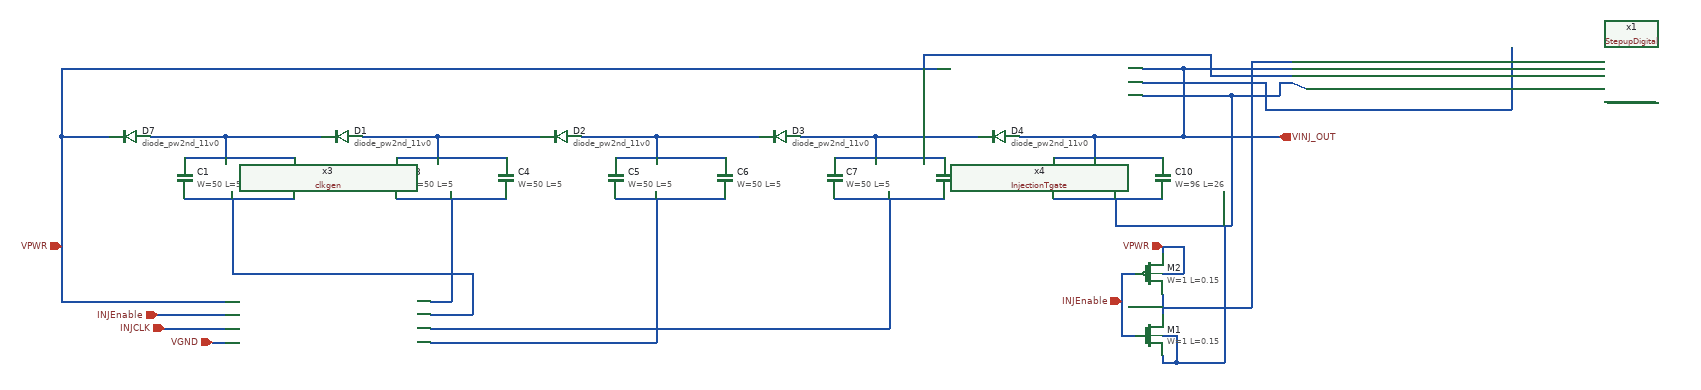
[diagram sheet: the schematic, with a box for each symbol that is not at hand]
v {xschem version=3.4.5 file_version=1.2
}
G {}
K {}
V {}
S {}
E {}
N -890 -680 -860 -680 { lab=VPWR}
N -800 -680 -780 -680 { lab=#net1}
N -740 -680 -710 -680 { lab=#net1}
N -780 -680 -740 -680 { lab=#net1}
N -750 -650 -590 -650 { lab=#net1}
N -750 -590 -590 -590 { lab=#net2}
N -710 -680 -690 -680 { lab=#net1}
N -690 -680 -690 -650 { lab=#net1}
N -580 -680 -550 -680 { lab=#net1}
N -490 -680 -470 -680 { lab=#net3}
N -430 -680 -400 -680 { lab=#net3}
N -470 -680 -430 -680 { lab=#net3}
N -440 -650 -280 -650 { lab=#net3}
N -440 -590 -280 -590 { lab=#net4}
N -400 -680 -380 -680 { lab=#net3}
N -380 -680 -380 -650 { lab=#net3}
N -380 -680 -260 -680 { lab=#net3}
N -690 -680 -580 -680 { lab=#net1}
N -260 -680 -230 -680 { lab=#net3}
N -170 -680 -150 -680 { lab=#net5}
N -110 -680 -80 -680 { lab=#net5}
N -150 -680 -110 -680 { lab=#net5}
N -120 -650 40 -650 { lab=#net5}
N -120 -590 40 -590 { lab=#net6}
N -80 -680 -60 -680 { lab=#net5}
N -60 -680 -60 -650 { lab=#net5}
N -60 -680 60 -680 { lab=#net5}
N 60 -680 90 -680 { lab=#net5}
N 150 -680 170 -680 { lab=#net7}
N 210 -680 240 -680 { lab=#net7}
N 170 -680 210 -680 { lab=#net7}
N 200 -650 360 -650 { lab=#net7}
N 200 -590 360 -590 { lab=#net8}
N 240 -680 260 -680 { lab=#net7}
N 260 -680 260 -650 { lab=#net7}
N 260 -680 380 -680 { lab=#net7}
N 380 -680 410 -680 { lab=#net7}
N 470 -680 490 -680 { lab=VINJ_OUT}
N 530 -680 560 -680 { lab=VINJ_OUT}
N 490 -680 530 -680 { lab=VINJ_OUT}
N 520 -650 680 -650 { lab=VINJ_OUT}
N 520 -590 680 -590 { lab=#net9}
N 560 -680 580 -680 { lab=VINJ_OUT}
N 580 -680 580 -650 { lab=VINJ_OUT}
N 580 -680 700 -680 { lab=VINJ_OUT}
N 650 -780 710 -780 { lab=VINJ_OUT}
N 710 -780 710 -680 { lab=VINJ_OUT}
N 700 -680 710 -680 { lab=VINJ_OUT}
N 650 -740 780 -740 { lab=#net9}
N 780 -740 780 -550 { lab=#net9}
N 610 -550 780 -550 { lab=#net9}
N 610 -590 610 -550 { lab=#net9}
N 710 -680 850 -680 { lab=VINJ_OUT}
N -930 -780 350 -780 { lab=VPWR}
N -930 -780 -930 -680 { lab=VPWR}
N -930 -680 -890 -680 { lab=VPWR}
N 710 -780 870 -780 { lab=VINJ_OUT}
N 830 -720 1030 -720 { lab=#net10}
N 830 -760 830 -720 { lab=#net10}
N 660 -760 830 -760 { lab=#net10}
N 650 -760 660 -760 { lab=#net10}
N 750 -770 870 -770 { lab=VPWR}
N 750 -800 750 -770 { lab=VPWR}
N 330 -800 750 -800 { lab=VPWR}
N 330 -800 330 -780 { lab=VPWR}
N 780 -740 850 -740 { lab=#net9}
N 850 -760 850 -740 { lab=#net9}
N 850 -760 870 -760 { lab=#net9}
N -390 -420 -330 -420 { lab=#net2}
N -330 -480 -330 -420 { lab=#net2}
N -680 -480 -330 -480 { lab=#net2}
N -680 -590 -680 -480 { lab=#net2}
N -390 -440 -360 -440 { lab=#net4}
N -360 -590 -360 -440 { lab=#net4}
N -390 -380 -60 -380 { lab=#net6}
N -60 -590 -60 -380 { lab=#net6}
N -390 -400 280 -400 { lab=#net8}
N 280 -590 280 -400 { lab=#net8}
N -930 -680 -930 -450 { lab=VPWR}
N -930 -450 -930 -440 { lab=VPWR}
N -930 -440 -690 -440 { lab=VPWR}
N 810 -790 870 -790 { lab=#net11}
N -790 -420 -690 -420 { lab=INJEnable}
N -710 -380 -690 -380 { lab=VGND}
N -780 -400 -690 -400 { lab=INJCLK}
N 680 -450 680 -420 { lab=#net11}
N 680 -480 710 -480 { lab=VPWR}
N 710 -520 710 -480 { lab=VPWR}
N 680 -520 710 -520 { lab=VPWR}
N 680 -520 680 -510 { lab=VPWR}
N 680 -390 700 -390 { lab=#net9}
N 700 -390 700 -350 { lab=#net9}
N 680 -350 700 -350 { lab=#net9}
N 680 -360 680 -350 { lab=#net9}
N 620 -480 640 -480 { lab=INJEnable}
N 620 -480 620 -390 { lab=INJEnable}
N 620 -390 640 -390 { lab=INJEnable}
N 680 -430 810 -430 { lab=#net11}
N 810 -790 810 -430 { lab=#net11}
N 770 -550 770 -350 { lab=#net9}
N 700 -350 770 -350 { lab=#net9}
N 1330 -730 1400 -730 {
lab=#net12}
N 1190 -810 1190 -720 {
lab=#net10}
N 1030 -720 1190 -720 {
lab=#net10}
N 870 -760 890 -750 {
lab=#net9}
C {sky130_fd_pr/cap_mim_m3_1.sym} -750 -620 0 0 {name=C1 model=cap_mim_m3_1 W=50 L=5 MF=1 spiceprefix=X}
C {sky130_fd_pr/cap_mim_m3_2.sym} -590 -620 2 0 {name=C2 model=cap_mim_m3_2 W=50 L=5 MF=1 spiceprefix=X}
C {sky130_fd_pr/lvsdiode.sym} -830 -680 1 0 {name=D7
model=diode_pw2nd_11v0


area=6.831}
C {sky130_fd_pr/cap_mim_m3_1.sym} -440 -620 0 0 {name=C3 model=cap_mim_m3_1 W=50 L=5 MF=1 spiceprefix=X}
C {sky130_fd_pr/cap_mim_m3_2.sym} -280 -620 2 0 {name=C4 model=cap_mim_m3_2 W=50 L=5 MF=1 spiceprefix=X}
C {sky130_fd_pr/cap_mim_m3_1.sym} -120 -620 0 0 {name=C5 model=cap_mim_m3_1 W=50 L=5 MF=1 spiceprefix=X}
C {sky130_fd_pr/cap_mim_m3_2.sym} 40 -620 2 0 {name=C6 model=cap_mim_m3_2 W=50 L=5 MF=1 spiceprefix=X}
C {sky130_fd_pr/cap_mim_m3_1.sym} 200 -620 0 0 {name=C7 model=cap_mim_m3_1 W=50 L=5 MF=1 spiceprefix=X}
C {sky130_fd_pr/cap_mim_m3_2.sym} 360 -620 2 0 {name=C8 model=cap_mim_m3_2 W=50 L=5 MF=1 spiceprefix=X}
C {sky130_fd_pr/cap_mim_m3_1.sym} 520 -620 0 0 {name=C9 model=cap_mim_m3_1 W=96 L=26 MF=1 spiceprefix=X}
C {sky130_fd_pr/cap_mim_m3_2.sym} 680 -620 2 0 {name=C10 model=cap_mim_m3_2 W=96 L=26 MF=1 spiceprefix=X}
C {sky130_fd_pr/lvsdiode.sym} -520 -680 1 0 {name=D1
model=diode_pw2nd_11v0


area=6.831}
C {sky130_fd_pr/lvsdiode.sym} -200 -680 1 0 {name=D2
model=diode_pw2nd_11v0


area=6.831}
C {sky130_fd_pr/lvsdiode.sym} 120 -680 1 0 {name=D3
model=diode_pw2nd_11v0


area=6.831}
C {sky130_fd_pr/lvsdiode.sym} 440 -680 1 0 {name=D4
model=diode_pw2nd_11v0
area=6.831


}
C {sky130_cells/ChargePump/InjectionTgate.sym} 500 -760 0 1 {name=x4}
C {sky130_cells/ChargePump/StepupDigital.sym} 1040 -780 0 0 {name=x1}
C {opin.sym} 850 -680 0 0 {name=p9 lab=VINJ_OUT}
C {ipin.sym} -930 -520 0 0 {name=p10 lab=VPWR}
C {ipin.sym} -710 -380 0 0 {name=p4 lab=VGND}
C {ipin.sym} -780 -400 0 0 {name=p5 lab=INJCLK}
C {ipin.sym} -790 -420 0 0 {name=p3 lab=INJEnable}
C {sky130_cells/ChargePump/clkgen.sym} -540 -410 0 0 {name=x3}
C {sky130_fd_pr/nfet_01v8.sym} 660 -390 0 0 {name=M1
L=0.15
W=1  
nf=1 mult=1
model=nfet_01v8
spiceprefix=X
}
C {sky130_fd_pr/pfet_01v8_hvt.sym} 660 -480 0 0 {name=M2
L=0.15
W=1
nf=1 mult=1
model=pfet_01v8_hvt
spiceprefix=X
}
C {ipin.sym} 680 -520 0 0 {name=p2 lab=VPWR}
C {ipin.sym} 620 -440 0 0 {name=p6 lab=INJEnable}
